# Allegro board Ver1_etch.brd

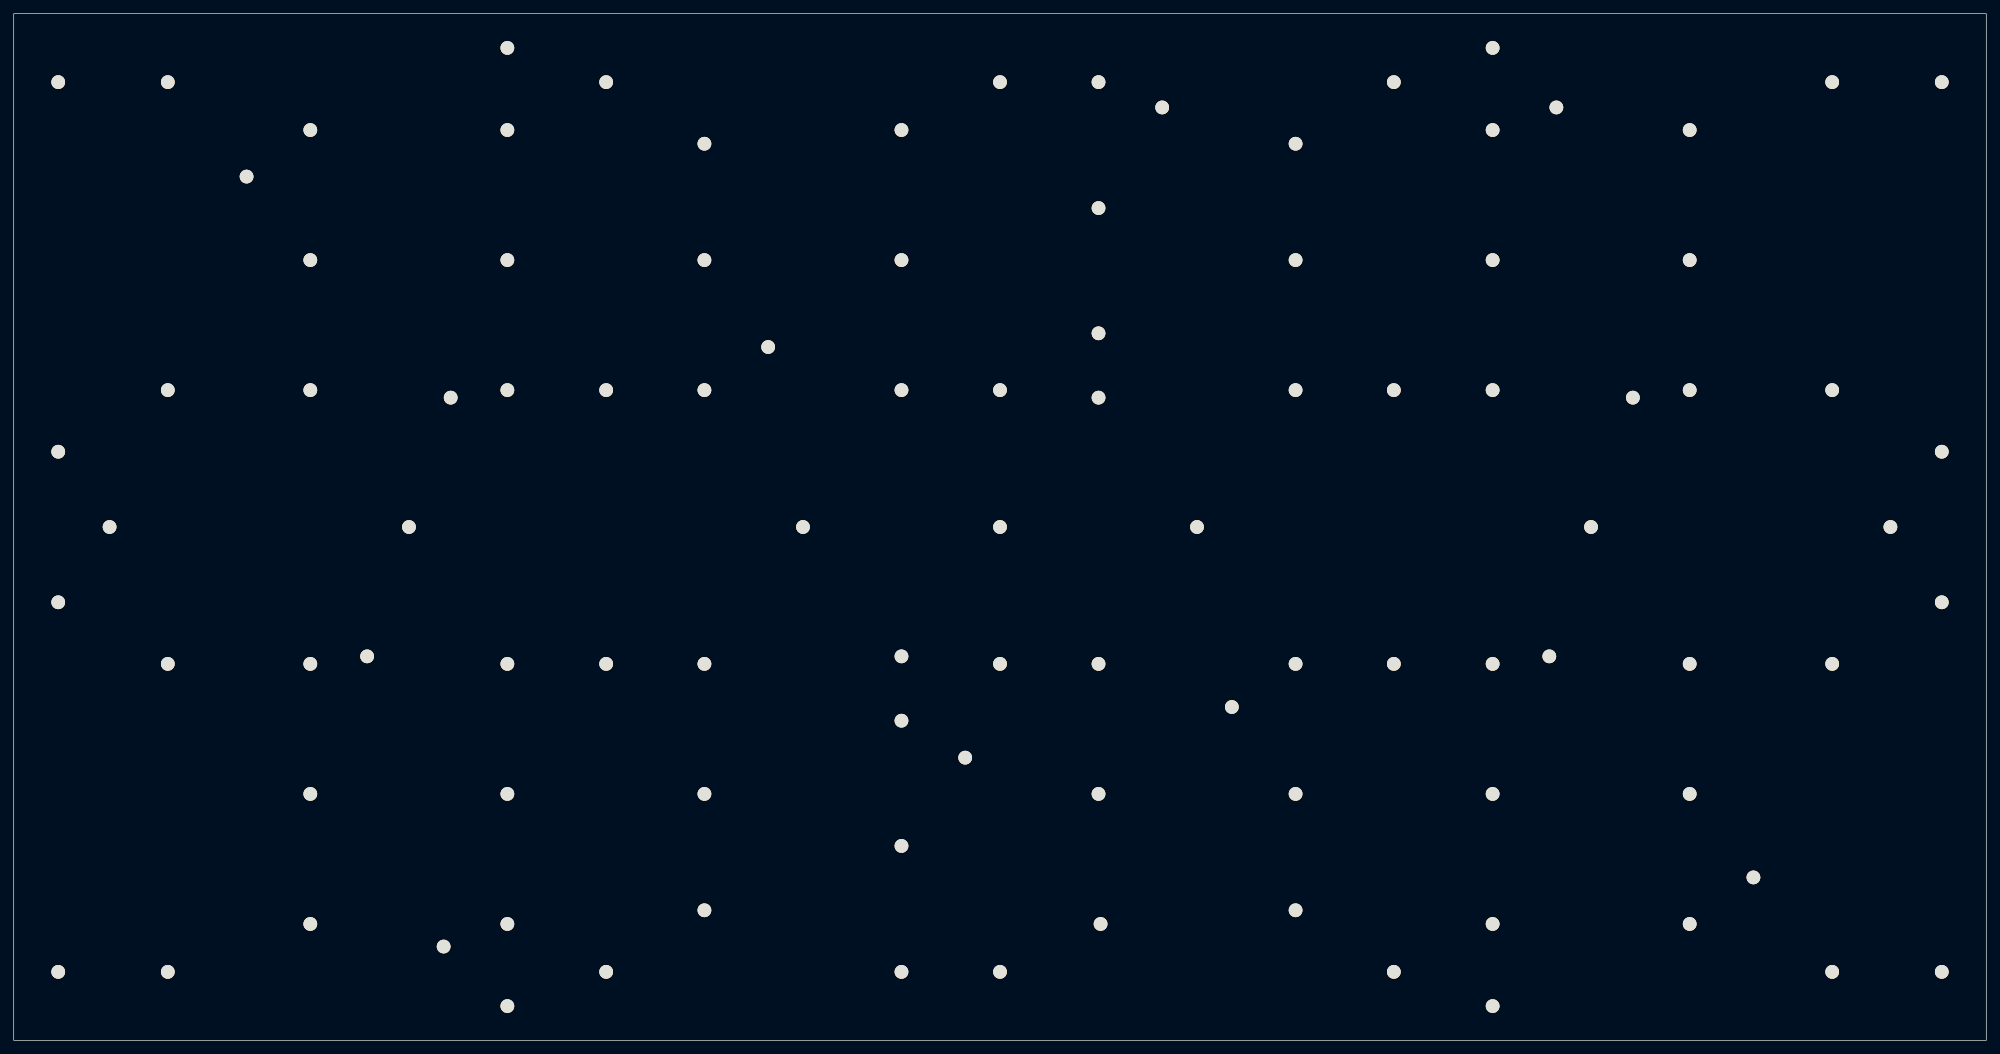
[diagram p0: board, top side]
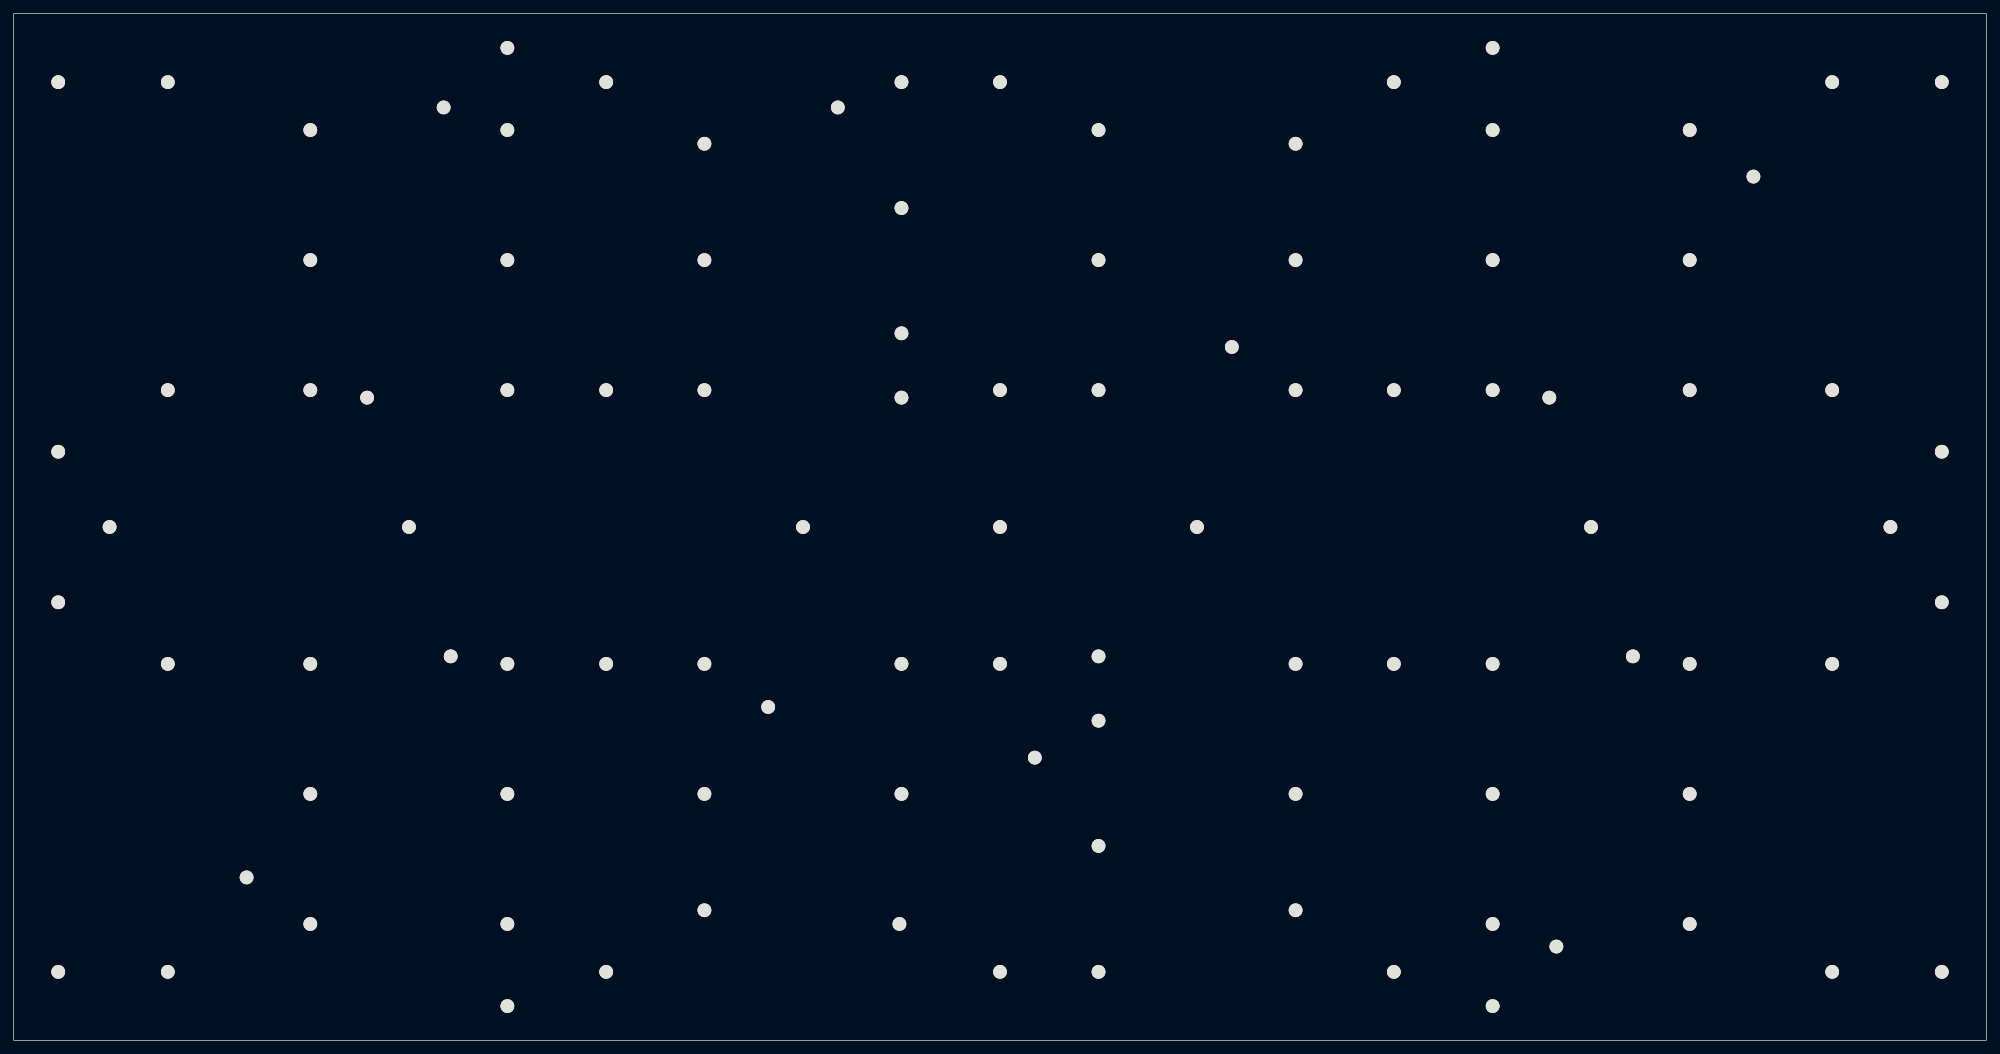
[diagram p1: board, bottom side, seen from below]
Outline 288 x 150 mm; copper layers: TOP, BOTTOM. Coordinates in mm from the lower left corner of the outline.
Outline path: rectangle 0,0 288,150

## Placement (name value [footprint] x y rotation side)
NOREF  -  [unnamed]  215.93 5 0 top
NOREF#2  -  [unnamed]  158.38 36 0 top
NOREF#3  -  [unnamed]  115.24 75 0 top
NOREF#4  -  [unnamed]  281.5 64 0 top
NOREF#5  -  [unnamed]  57.71 75 0 top
NOREF#6  -  [unnamed]  129.62 46.7 0 top
NOREF#7  -  [unnamed]  158.38 103.3 0 top
NOREF#8  -  [unnamed]  158.38 93.9 0 top
NOREF#9  -  [unnamed]  177.85 48.7 0 top
NOREF#10  -  [unnamed]  265.5 55 0 top
NOREF#11  -  [unnamed]  6.5 86 0 top
NOREF#12  -  [unnamed]  100.84 55 0 top
NOREF#13  -  [unnamed]  62.77 13.7 0 top
NOREF#14  -  [unnamed]  244.69 55 0 top
NOREF#15  -  [unnamed]  129.62 28.4 0 top
NOREF#16  -  [unnamed]  72.08 133 0 top
NOREF#17  -  [unnamed]  6.5 64 0 top
NOREF#18  -  [unnamed]  100.84 36 0 top
NOREF#19  -  [unnamed]  187.16 36 0 top
NOREF#20  -  [unnamed]  187.16 55 0 top
NOREF#21  -  [unnamed]  281.5 10 0 top
NOREF#22  -  [unnamed]  274 75 0 top
NOREF#23  -  [unnamed]  244.69 36 0 top
NOREF#24  -  [unnamed]  22.5 10 0 top
NOREF#25  -  [unnamed]  43.31 133 0 top
NOREF#26  -  [unnamed]  100.84 95 0 top
NOREF#27  -  [unnamed]  129.62 114 0 top
NOREF#28  -  [unnamed]  236.4 93.9 0 top
NOREF#29  -  [unnamed]  201.5 55 0 top
NOREF#30  -  [unnamed]  138.92 41.3 0 top
NOREF#31  -  [unnamed]  43.31 17 0 top
NOREF#32  -  [unnamed]  201.5 140 0 top
NOREF#33  -  [unnamed]  129.62 133 0 top
NOREF#34  -  [unnamed]  129.62 56.1 0 top
NOREF#35  -  [unnamed]  72.08 55 0 top
NOREF#36  -  [unnamed]  22.5 95 0 top
NOREF#37  -  [unnamed]  72.08 114 0 top
NOREF#38  -  [unnamed]  244.69 133 0 top
NOREF#39  -  [unnamed]  100.84 114 0 top
NOREF#40  -  [unnamed]  265.5 10 0 top
NOREF#41  -  [unnamed]  6.5 10 0 top
NOREF#42  -  [unnamed]  215.93 133 0 top
NOREF#43  -  [unnamed]  187.16 95 0 top
NOREF#44  -  [unnamed]  100.84 19 0 top
NOREF#45  -  [unnamed]  172.76 75 0 top
NOREF#46  -  [unnamed]  215.93 95 0 top
NOREF#47  -  [unnamed]  86.5 55 0 top
NOREF#48  -  [unnamed]  22.5 55 0 top
NOREF#49  -  [unnamed]  72.08 36 0 top
NOREF#50  -  [unnamed]  144 95 0 top
NOREF#51  -  [unnamed]  224.2 56.1 0 top
NOREF#52  -  [unnamed]  215.93 36 0 top
NOREF#53  -  [unnamed]  72.08 5 0 top
NOREF#54  -  [unnamed]  86.5 95 0 top
NOREF#55  -  [unnamed]  187.16 19 0 top
NOREF#56  -  [unnamed]  129.62 95 0 top
NOREF#57  -  [unnamed]  215.93 145 0 top
NOREF#58  -  [unnamed]  51.6 56.1 0 top
NOREF#59  -  [unnamed]  201.5 10 0 top
NOREF#60  -  [unnamed]  215.93 114 0 top
NOREF#61  -  [unnamed]  63.8 93.9 0 top
NOREF#62  -  [unnamed]  215.93 55 0 top
NOREF#63  -  [unnamed]  230.29 75 0 top
NOREF#64  -  [unnamed]  6.5 140 0 top
NOREF#65  -  [unnamed]  34 126.2 0 top
NOREF#66  -  [unnamed]  281.5 140 0 top
NOREF#67  -  [unnamed]  144 55 0 top
NOREF#68  -  [unnamed]  43.31 36 0 top
NOREF#69  -  [unnamed]  22.5 140 0 top
NOREF#70  -  [unnamed]  187.16 114 0 top
NOREF#71  -  [unnamed]  86.5 140 0 top
NOREF#72  -  [unnamed]  14 75 0 top
NOREF#73  -  [unnamed]  265.5 95 0 top
NOREF#74  -  [unnamed]  43.31 114 0 top
NOREF#75  -  [unnamed]  244.69 95 0 top
NOREF#76  -  [unnamed]  244.69 114 0 top
NOREF#77  -  [unnamed]  265.5 140 0 top
NOREF#78  -  [unnamed]  43.31 55 0 top
NOREF#79  -  [unnamed]  72.08 145 0 top
NOREF#80  -  [unnamed]  100.84 131 0 top
NOREF#81  -  [unnamed]  158.38 121.6 0 top
NOREF#82  -  [unnamed]  167.68 136.3 0 top
NOREF#83  -  [unnamed]  110.15 101.3 0 top
NOREF#84  -  [unnamed]  225.23 136.3 0 top
NOREF#85  -  [unnamed]  158.38 140 0 top
NOREF#86  -  [unnamed]  281.5 86 0 top
NOREF#87  -  [unnamed]  158.38 55 0 top
NOREF#88  -  [unnamed]  144 140 0 top
NOREF#89  -  [unnamed]  144 75 0 top
NOREF#90  -  [unnamed]  144 10 0 top
NOREF#91  -  [unnamed]  43.31 95 0 top
NOREF#92  -  [unnamed]  215.93 17 0 top
NOREF#93  -  [unnamed]  86.5 10 0 top
NOREF#94  -  [unnamed]  72.08 17 0 top
NOREF#95  -  [unnamed]  244.69 17 0 top
NOREF#96  -  [unnamed]  254 23.8 0 top
NOREF#97  -  [unnamed]  201.5 95 0 top
NOREF#98  -  [unnamed]  72.08 95 0 top
NOREF#99  -  [unnamed]  129.62 10 0 top
NOREF#100  -  [unnamed]  187.16 131 0 top
NOREF#101  -  [unnamed]  158.69 17 0 top

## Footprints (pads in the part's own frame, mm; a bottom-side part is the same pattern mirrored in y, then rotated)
unnamed
  round 2 hole 8 unplated: (0,0)

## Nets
